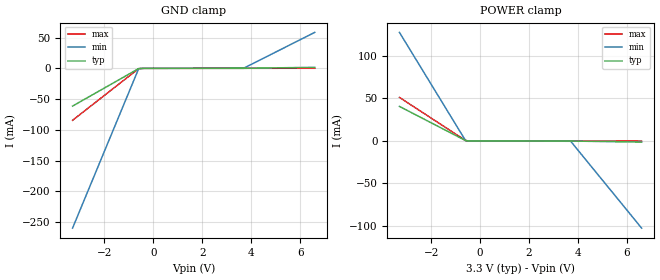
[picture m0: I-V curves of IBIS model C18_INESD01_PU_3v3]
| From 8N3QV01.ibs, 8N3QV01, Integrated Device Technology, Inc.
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[Model] C18_INESD01_PU_3v3
Model_type   Input
Polarity   Non-Inverting
Vinl = 0.8V
Vinh = 2.0V
|   typ   min   max
C_comp   2pF   1.5pF   2.5pF
|   typ   min   max
[Voltage range]   3.3V   3.135V   3.465V
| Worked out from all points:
|   GND clamp passes 1 mA (typ) near -0.62 V on its own axis
|   POWER clamp passes 1 mA (typ) near -0.63 V on its own axis
[GND_clamp]
|Voltage   I (typ)   I (min)   I (max)
-3.3V     -61.39mA   -259.7mA   -84.47mA
-2.9V     -52.37mA   -221.3mA   -72.05mA
-2.8V     -50.12mA   -211.7mA   -68.94mA
-2.3V     -38.84mA   -163.8mA   -53.41mA
-2.2V     -36.59mA   -154.2mA   -50.3mA
-1.2V     -14.05mA   -58.3mA    -19.24mA
-1.1V     -11.79mA   -48.71mA   -16.13mA
-600mV    -519.3uA   -757.2uA   -601.3uA
-400mV    -77.06uA   -71.62uA   -83.32uA
3.7V      11.34uA    280.9uA    4.99uA
6.2V      1.361mA    50.37mA    60.87uA
6.6V      1.577mA    58.38mA    69.81uA
[Power_clamp]
|Voltage   I (typ)   I (min)   I (max)
-3.3V     40.67mA    127.8mA    51.25mA
-2.5V     28.77mA    90.12mA    36.25mA
-2.4V     27.28mA    85.41mA    34.37mA
-2.1V     22.82mA    71.27mA    28.74mA
-2V       21.33mA    66.56mA    26.87mA
-1.2V     9.428mA    28.85mA    11.86mA
-1.1V     7.94mA     24.14mA    9.988mA
-600mV    501.9uA    575.2uA    609.4uA
-500mV    65.34uA    72.75uA    60.6uA
3.7V      -77.06uA   -358.2uA   -78.55uA
4.5V      -433.9uA   -28.56mA   -96.35uA
6.6V      -1.37mA    -102.6mA   -143uA
